VERSION 5.7 ;
  NOWIREEXTENSIONATPIN ON ;
  DIVIDERCHAR "/" ;
  BUSBITCHARS "[]" ;
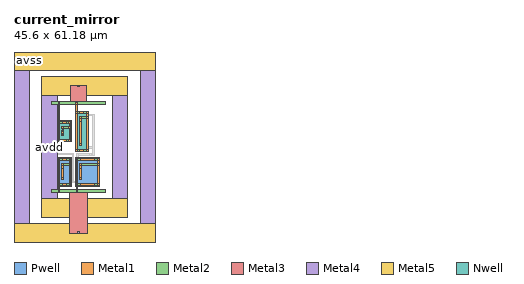
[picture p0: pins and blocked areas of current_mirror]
MACRO current_mirror
  CLASS BLOCK ;
  FOREIGN current_mirror ;
  ORIGIN 0.000 0.000 ;
  SIZE 45.600 BY 61.180 ;
  PIN avss
    USE GROUND ;
    ANTENNADIFFAREA 24.695999 ;
    PORT
      LAYER Pwell ;
        RECT 14.000 18.000 18.440 27.090 ;
        RECT 19.740 18.000 27.600 27.090 ;
      LAYER Metal1 ;
        RECT 14.230 26.380 14.730 26.880 ;
        RECT 15.570 26.380 16.870 26.880 ;
        RECT 17.710 26.380 18.210 26.880 ;
        RECT 14.230 18.710 14.690 26.380 ;
        RECT 17.750 25.190 18.210 26.380 ;
        RECT 15.400 24.690 15.900 25.190 ;
        RECT 17.710 24.690 18.210 25.190 ;
        RECT 15.420 23.590 15.880 24.690 ;
        RECT 15.400 20.690 15.900 23.590 ;
        RECT 15.420 20.140 15.880 20.690 ;
        RECT 17.750 18.710 18.210 24.690 ;
        RECT 14.230 18.210 14.730 18.710 ;
        RECT 15.570 18.210 16.870 18.710 ;
        RECT 17.710 18.210 18.210 18.710 ;
        RECT 19.970 26.380 20.470 26.880 ;
        RECT 21.420 26.380 25.920 26.880 ;
        RECT 26.870 26.380 27.370 26.880 ;
        RECT 19.970 18.710 20.430 26.380 ;
        RECT 26.910 25.190 27.370 26.380 ;
        RECT 21.140 24.690 21.640 25.190 ;
        RECT 26.870 24.690 27.370 25.190 ;
        RECT 21.160 23.590 21.620 24.690 ;
        RECT 21.140 20.690 21.640 23.590 ;
        RECT 21.160 20.140 21.620 20.690 ;
        RECT 26.910 18.710 27.370 24.690 ;
        RECT 19.970 18.210 20.470 18.710 ;
        RECT 21.420 18.210 25.920 18.710 ;
        RECT 26.870 18.210 27.370 18.710 ;
        RECT 14.230 16.750 14.690 18.210 ;
        RECT 19.970 16.750 20.430 18.210 ;
        RECT 14.230 16.250 14.730 16.750 ;
        RECT 19.970 16.250 20.470 16.750 ;
      LAYER Metal2 ;
        RECT 14.230 26.380 18.210 26.880 ;
        RECT 19.970 26.380 27.370 26.880 ;
        RECT 15.400 24.690 18.210 25.190 ;
        RECT 21.140 24.690 27.370 25.190 ;
        RECT 15.400 20.140 15.900 24.140 ;
        RECT 21.140 20.140 21.640 24.140 ;
        RECT 14.230 18.210 18.210 18.710 ;
        RECT 19.970 18.210 27.370 18.710 ;
        RECT 12.000 16.000 29.600 17.000 ;
      LAYER Metal3 ;
        RECT 17.800 2.750 23.800 16.750 ;
      LAYER Metal4 ;
        RECT 0.000 0.000 5.000 61.180 ;
        RECT 20.550 2.750 21.050 3.250 ;
        RECT 40.600 0.000 45.600 61.180 ;
      LAYER Metal5 ;
        RECT 0.000 55.180 45.600 61.180 ;
        RECT 0.000 0.000 45.600 6.000 ;
    END
  END avss
  PIN avdd
    USE POWER ;
    ANTENNADIFFAREA 23.630400 ;
    PORT
      LAYER Nwell ;
        RECT 14.040 32.290 18.400 38.980 ;
        RECT 19.700 29.090 24.060 42.180 ;
      LAYER Metal1 ;
        RECT 14.270 44.430 14.770 44.930 ;
        RECT 19.930 44.430 20.430 44.930 ;
        RECT 14.270 38.770 14.730 44.430 ;
        RECT 19.930 41.970 20.390 44.430 ;
        RECT 19.930 41.470 20.430 41.970 ;
        RECT 21.230 41.470 22.530 41.970 ;
        RECT 23.330 41.470 23.830 41.970 ;
        RECT 14.270 38.270 14.770 38.770 ;
        RECT 15.570 38.270 16.870 38.770 ;
        RECT 17.670 38.270 18.170 38.770 ;
        RECT 14.270 33.000 14.730 38.270 ;
        RECT 17.710 37.080 18.170 38.270 ;
        RECT 15.440 36.580 15.940 37.080 ;
        RECT 17.670 36.580 18.170 37.080 ;
        RECT 15.460 35.480 15.920 36.580 ;
        RECT 15.440 34.980 15.940 35.480 ;
        RECT 15.460 34.430 15.920 34.980 ;
        RECT 17.710 33.000 18.170 36.580 ;
        RECT 14.270 32.500 14.770 33.000 ;
        RECT 15.570 32.500 16.870 33.000 ;
        RECT 17.670 32.500 18.170 33.000 ;
        RECT 19.930 29.800 20.390 41.470 ;
        RECT 23.370 40.280 23.830 41.470 ;
        RECT 21.100 39.780 21.600 40.280 ;
        RECT 23.330 39.780 23.830 40.280 ;
        RECT 21.120 38.680 21.580 39.780 ;
        RECT 21.100 31.780 21.600 38.680 ;
        RECT 21.120 31.230 21.580 31.780 ;
        RECT 23.370 29.800 23.830 39.780 ;
        RECT 19.930 29.300 20.430 29.800 ;
        RECT 21.230 29.300 22.530 29.800 ;
        RECT 23.330 29.300 23.830 29.800 ;
      LAYER Metal2 ;
        RECT 12.000 44.180 29.600 45.180 ;
        RECT 19.930 41.470 23.830 41.970 ;
        RECT 21.100 39.780 23.830 40.280 ;
        RECT 14.270 38.270 18.170 38.770 ;
        RECT 15.440 36.580 18.170 37.080 ;
        RECT 15.440 34.430 15.940 36.030 ;
        RECT 14.270 32.500 18.170 33.000 ;
        RECT 21.100 31.230 21.600 39.230 ;
        RECT 19.930 29.300 23.830 29.800 ;
      LAYER Metal3 ;
        RECT 18.300 44.430 23.300 50.430 ;
      LAYER Metal4 ;
        RECT 9.000 8.000 14.000 53.180 ;
        RECT 20.550 49.930 21.050 50.430 ;
        RECT 31.600 8.000 36.600 53.180 ;
      LAYER Metal5 ;
        RECT 9.000 47.180 36.600 53.180 ;
        RECT 9.000 8.000 36.600 14.000 ;
    END
  END avdd
  OBS
      LAYER Metal1 ;
        RECT 22.160 40.580 22.660 41.080 ;
        RECT 22.180 38.680 22.640 40.580 ;
        RECT 16.500 37.380 17.000 37.880 ;
        RECT 16.520 35.480 16.980 37.380 ;
        RECT 16.500 34.980 17.000 35.480 ;
        RECT 16.520 34.430 16.980 34.980 ;
        RECT 15.970 33.390 16.470 33.890 ;
        RECT 22.160 31.780 22.660 38.680 ;
        RECT 22.180 31.230 22.640 31.780 ;
        RECT 21.630 30.190 22.130 30.690 ;
        RECT 16.540 25.490 17.040 25.990 ;
        RECT 25.700 25.490 26.200 25.990 ;
        RECT 16.560 23.590 17.020 25.490 ;
        RECT 25.720 23.590 26.180 25.490 ;
        RECT 16.540 20.690 17.040 23.590 ;
        RECT 25.700 20.690 26.200 23.590 ;
        RECT 16.560 20.140 17.020 20.690 ;
        RECT 25.720 20.140 26.180 20.690 ;
        RECT 15.970 19.100 16.470 19.600 ;
        RECT 22.220 19.100 22.720 19.600 ;
        RECT 23.020 19.100 23.520 19.600 ;
        RECT 23.820 19.100 24.320 19.600 ;
        RECT 24.620 19.100 25.120 19.600 ;
      LAYER Metal2 ;
        RECT 21.100 40.580 25.930 41.080 ;
        RECT 13.470 37.380 17.000 37.880 ;
        RECT 16.500 34.430 17.000 36.030 ;
        RECT 13.470 33.390 16.470 33.890 ;
        RECT 22.160 31.230 22.660 39.230 ;
        RECT 21.630 30.190 25.930 30.690 ;
        RECT 13.470 28.140 19.270 28.640 ;
        RECT 20.140 27.940 25.930 28.440 ;
        RECT 13.470 25.490 17.040 25.990 ;
        RECT 20.140 25.490 26.200 25.990 ;
        RECT 16.540 20.140 17.040 24.140 ;
        RECT 25.700 20.140 26.200 24.140 ;
        RECT 13.470 19.100 16.470 19.600 ;
        RECT 18.770 19.100 25.670 19.600 ;
      LAYER Metal3 ;
        RECT 13.470 19.100 13.970 37.880 ;
        RECT 18.520 28.140 19.270 28.640 ;
        RECT 18.770 19.100 19.270 28.140 ;
        RECT 20.140 25.490 20.640 28.440 ;
        RECT 24.180 27.940 24.930 28.440 ;
        RECT 25.430 27.940 25.930 41.080 ;
  END
END current_mirror
END LIBRARY

